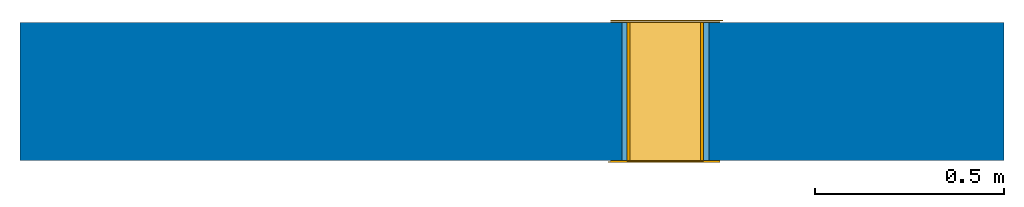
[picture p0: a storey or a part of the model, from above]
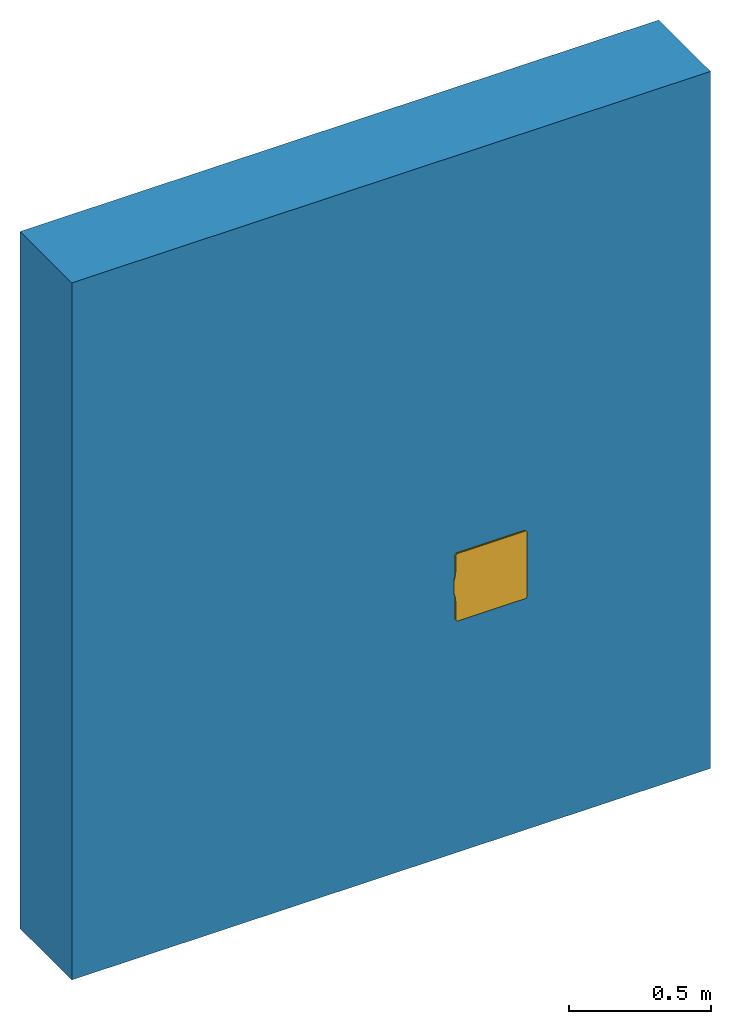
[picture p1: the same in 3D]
Properties of the parts of a building model (IFC2X3)

# File
Description: ViewDefinition [CoordinationView_V2.0], RevitIdentifiers [ContentGUID: 705172e0-cb51-4237-a813-d543770cc92d, VersionGUID: ee3a34b3-1578-43ea-a0d7-5f81ac734b6b, NumberOfSaves: 9], CoordinateReference [CoordinateBase: Gemeinsam genutzte Koordinaten]
File name: Labolite.ifc
Time: 2025-02-09T17:17:46+01:00
Written by: ODA SDAI 24.6
Made in: Autodesk Revit 24.3.10.22 (DEU) - IFC 24.3.10.22

# IfcProject, 2018_01
Phase: Projekt Status

# IfcSite, Default
RefLatitude: 48, 8, 15, 359802; RefLongitude: 11, 34, 47, 783432; RefElevation: 0 m

# IfcWallStandardCase: Basiswand:Ziegel 365, Basiswand:Ziegel 365:2441351
In: Default
Type - PredefinedType: STANDARD; Material: Mauerwerk - Ziegel 0.365 m
Type - Pset_WallCommon - ThermalTransmittance: 1.47945 kg/K/s3
Pset_QuantityTakeOff - Reference: Ziegel 365; sets with these values: 2
Pset_WallCommon - Reference: Ziegel 365; IsExternal: yes; ExtendToStructure: no; LoadBearing: no

# IfcWindow: LaboLite:LaboLite Modell Wandöffnung 230x230, LaboLite:LaboLite Modell Wandöffnung 230x230:2455149
In: Default
Type - ParameterTakesPrecedence: no; Sizeable: no; Material: Polyethylen-Kern, Aluminiumverbundplatte RAL 9003 / 9006
Type - Pset_ManufacturerTypeInformation - Manufacturer: Urindurchreiche
OverallHeight: 0.23 m; OverallWidth: 0.23 m
Pset_QuantityTakeOff - Reference: LaboLite Modell Wandöffnung 230x230
Pset_WindowCommon - IsExternal: yes; Reference: LaboLite Modell Wandöffnung 230x230
